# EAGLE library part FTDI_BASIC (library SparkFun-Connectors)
FTDI Basic header with labels

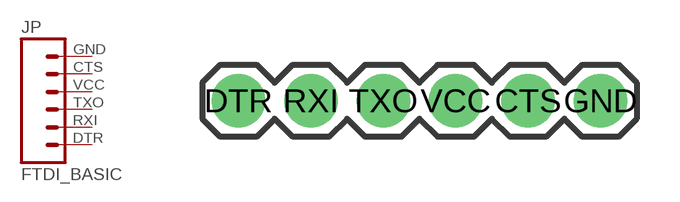
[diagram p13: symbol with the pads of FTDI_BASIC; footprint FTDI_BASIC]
Designator prefix JP

## FTDI_BASICPTH  [FTDI_BASIC]
CTS  5  pas
DTR  1  pas
GND  6  pas
RXI  2  pas
TXO  3  pas
VCC  4  pas

## Footprint FTDI_BASIC (pad centres in mm)
drill 1.016 pad 1.88: CTS 10.16,0; DTR 0,0; GND 12.7,0; RXI 2.54,0; TXO 5.08,0; VCC 7.62,0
